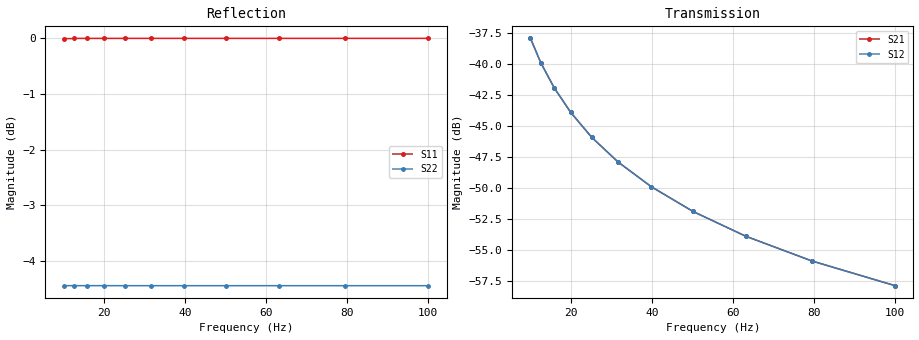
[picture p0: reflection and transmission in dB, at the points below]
[Version] 2.0
# Hz Y RI R 50
[Number of Ports] 2
[Two-Port Data Order] 12_21
[Reference] 50 50
! 11 data lines when there should be 10
!  Freq  ReY11  ImY11  ReY12  ImY12  ReY21  ImY21  ReY22  ImY22
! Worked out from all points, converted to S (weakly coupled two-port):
!   11 points, 10 Hz to 100 Hz, reference 50 ohm
!   highest |S21| = -37.91 dB at 10 Hz (marker M1); lowest = -57.9 dB at 100 Hz (marker M2)
!   lowest |S11| = 0.0 dB at 10 Hz (marker M3)
!   |S11| at or under -10 dB: nowhere
!   |S22| runs from -4.4 to -4.4 dB; largest |S21 - S12| = 3.4e-17
[Number of Frequencies] 11
[Network Data]
10  0.0129 0.6281  -0.005 6.28e-05  -0.005 6.28e-05  0.005 6.53e-09
12.58925  0.0175 0.7907  -0.005 7.91e-05  -0.005 7.91e-05  0.005 8.22e-09
15.84893  0.0248 0.9952  -0.005 9.95e-05  -0.005 9.95e-05  0.005 1.03e-08
19.95262  0.0364 1.253  -0.005 0.000125  -0.005 0.000125  0.005 1.3e-08
25.11886  0.0548 1.576  -0.00499 0.000158  -0.00499 0.000158  0.005 1.64e-08
31.62278  0.0838 1.983  -0.00499 0.000198  -0.00499 0.000198  0.005 2.06e-08
39.81072  0.1298 2.495  -0.00499 0.000249  -0.00499 0.000249  0.005 2.59e-08
50.11872  0.2025 3.136  -0.00498 0.000314  -0.00498 0.000314  0.005 3.26e-08
63.09573  0.3173 3.939  -0.00497 0.000394  -0.00497 0.000394  0.005 4.1e-08
79.43282  0.4981 4.941  -0.00495 0.000494  -0.00495 0.000494  0.005 5.14e-08
100  0.7821 6.184  -0.00492 0.000618  -0.00492 0.000618  0.005 6.43e-08
[End]
